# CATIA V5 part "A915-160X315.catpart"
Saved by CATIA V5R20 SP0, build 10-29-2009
Part number: A915-160X315
Source: Unknown
Property "A": "110.000"
Property "ARTICLENO": "A915-160X315"
Property "BOMINFO": "A915-160X315"
Property "CODE": "A915-160X315"
Property "CREATOR": "CADENAS GmbH"
Property "D": "13.500"
Property "D1": "20.000"
Property "FORM": "D"
Property "L": "315.000"
Property "L1": "40.000"
Property "L2": "235.000"
Property "LINA": "A915-160X315"
Property "NB": "A915-160X315"
Property "NBSYN": "$CODE."
Property "NN": "A915"
Property "NT": "VDI 3357 Wear Plates, steel"
Property "SCREW": "M12x25"
Property "SUPPLIER": "CF"
Property "T": "13.000"
Property "W": "160.000"
Bounding box of the stored display mesh (mm): x 0 to 20, y 0 to 315, z -80 to 80
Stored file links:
  C:\Users\borellobunino\Desktop\3D X SITO CF\A915\GSB_OILLESS_G22501160315\CATIAV5\A915-160X315.catpart

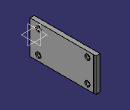
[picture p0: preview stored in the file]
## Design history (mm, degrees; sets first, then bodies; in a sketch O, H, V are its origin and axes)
Body1 "Geometry.1" (main body)
  Solid1 "A915-160X315.catpart": solid without history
